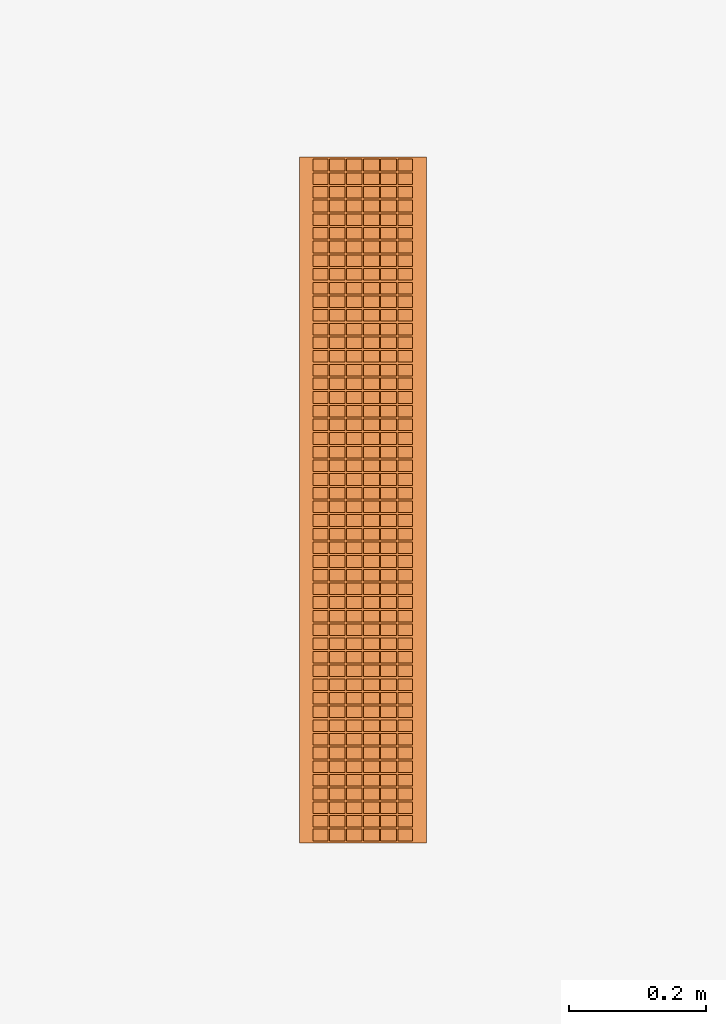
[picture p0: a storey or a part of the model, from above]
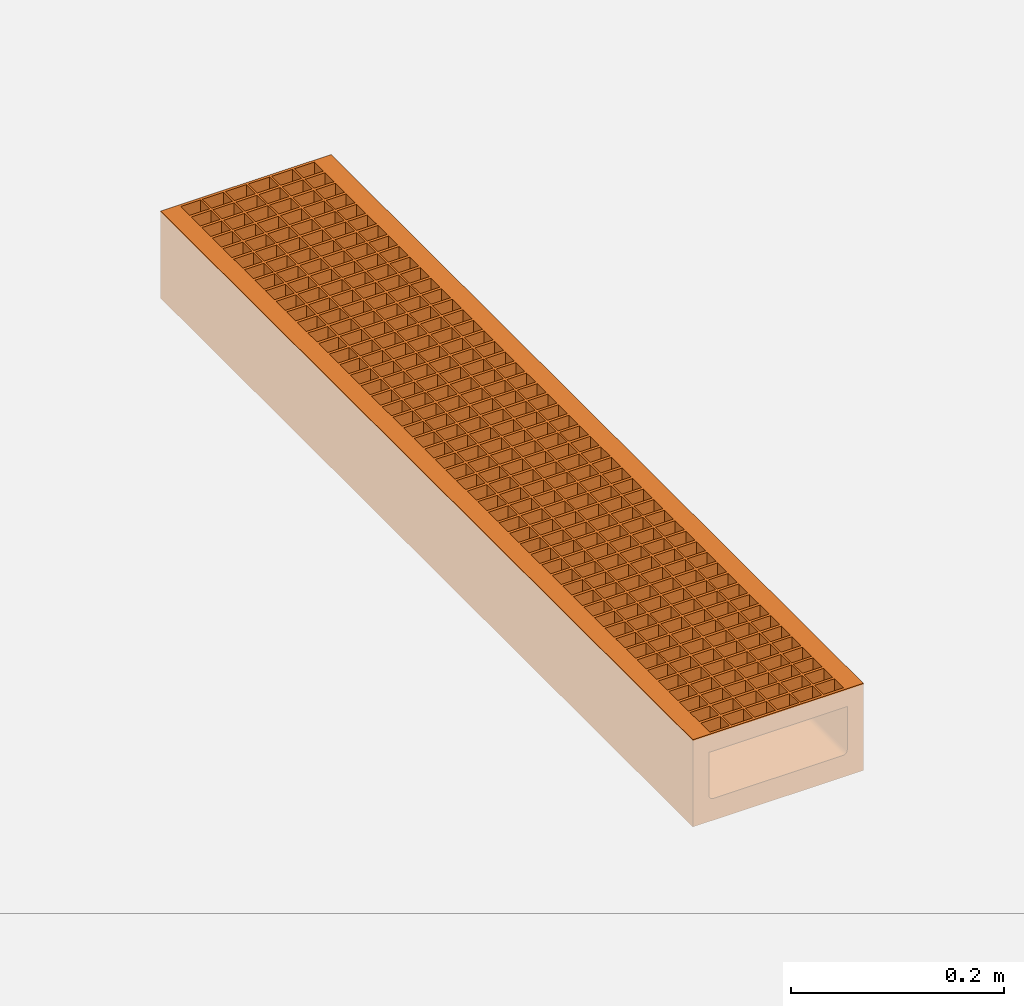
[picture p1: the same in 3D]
Properties of the parts of a building model (IFC2X3)

# File
Description: ViewDefinition [CoordinationView]
File name: 24156 - No 0100 Constant Depth Channel - 1000mm LG - Invert Depth 75mm.ifc
Time: 2013-10-17T16:58:12
Written by: Autodesk Revit 2013
Made in: 20120221_2030(x64)

# IfcProject, Project Number
LongName: Project Name; Phase: Project Status

# IfcSite, Default
RefLatitude: 42, 21, 30, 344238; RefLongitude: -71, -3, -35, -194702; RefElevation: 0 mm

# IfcBuilding
Pset_BuildingCommon - NumberOfStoreys: 1
Other - Project Number: Project Number; Project Address: ## Street City, State Zip; Project Issue Date: Issue Date; Project Status: Project Status; Project Name: Project Name; Client Name: Owner

# IfcBuildingStorey, Level 1
LongName: Level 1; Elevation: 0 mm
Constraints - Elevation Base: 0; Elevation: 0 mm
Graphics - Symbol at End 1 Default: no; Symbol at End 2 Default: yes; Line Pattern: Center; Line Weight: 1; Color: 0; Symbol: M_Level Head - Circle: M_Level Head - Circle
Identity Data - Name: Level 1; Structural: no; Building Story: yes
Dimensions - Computation Height: 0 mm

# IfcBuildingElementProxy: 24156 - No 0100 Constant Depth Channel - 1000mm LG - Invert Depth 75mm, Civil-Drainage-Channel-ACO-MultiDrain-M150DS-Channel-System-Custom_Final FL:24156 - No 0100 Constant Depth Channel - 1000mm LG - Invert Depth 75mm:24156 - No 0100 Constant Depth Channel - 1000mm LG - Invert Depth 75mm:199235
In: Level 1
Material: Vienite® Synthetic Resin Concrete
Constraints - Moves With Nearby Elements: no; Level: Level: Level 1
Phasing - Phase Created: New Construction
Construction - 13048 - Grating - Mesh - Stainless Steel - 1000mm Long: no; 23159 - Universal Endcap (Female End): no; 13049 - Grating - Mesh - Stainless Steel - 500mm Long: no; 23159 - Universal Endcap (Male End): no; Grating_500mm: no; 24157_Shallow Depth Channel with seal: no; Grating_1000mm: yes; Constant Depth Channel_1000: no; 24156_Shallow Depth Channel: yes; Constant Depth Channel_500: no; 24158_Sump Unit: no
Dimensions - EndCap Position: 1000 mm; FloorCut_Length: -1000 mm; Volume: 8023029 mm3; Length: 1000 mm; Custom cut void length: 0 mm; Depth: 310 mm; EndCap_Height: 100 mm; Mesh grating length: -1000 mm; InvDepth: 210 mm; FloorCut_Depth: 100 mm; FloorCut_HorPosition: 92.5 mm; FloorCut_Width: 185 mm
Pset_BuildingElementProxyCommon - Reference: 24156 - No 0100 Constant Depth Channel - 1000mm LG - Invert Depth 75mm
Data - Installation - Concrete Grade: Refer to brochure; Concrete Surround Volume - Load Class A 15 - Concrete Pavement: 0.06m³/m; Invert Depth: 75mm; Product Weight: 16.7Kg; Concrete Surround Volume - Load Class B 125 - C 250 - Concrete Pavement: 0.10m³/m; Load Class: A 15 - D 400; Channel C.S.A: 0.008m²; Concrete Surround Volume - Load Class D 400 - Concrete Pavement: 0.16m³/m; Pre-formed Outlet Ø: N/A; Hydraulic Performance: http://www.aco.co.uk/download.php?id=173; Product Dimensions: 1000mm x 185mm x 100mm (LxWxH); Product Standard: BS EN 1433:2002, CE marked; ACO Hydraulic Design Software: http://www.acodesign.co.uk
General - TagNumber: 0; SerialNumber: 0
Identity Data - Watermark 1: This file is the property of ACO Technologies PLC; Fax: +44 (0)1462 815895; Product brochure: http://www.aco.co.uk/download.php?id=173; e-mail Sales: customersupport@aco.co.uk; Assembly Code: D2040; Telephone: +44 (0)1462 816666; Installation guidelines: http://www.aco.co.uk/download.php?id=173; Manufacturer: ACO Technologies plc - ACO Water Management Division; Address: ACO Business Park, Hitchin Road, Shefford, Bedfordshire, United Kingdom SG17 5TE; Product Page URL: http://www.aco.co.uk/product_detail.php?id=15; Watermark 2: This file is water marked and users are prohibited to reproduce, adapt, distribute this information; Assembly Description: Rain Water Drainage; Type Comments: ACO MultiDrain M150DS 0100 Shallow Constant Depth Channel 1000mm Long; Model Description: Channel drainage system; Watermarked By: www.aco.co.uk; Watermarked With: BIM Manager Premium Suite; Cost: 0; e-mail Technical: technical@aco.co.uk; OmniClass Title: Rainwater Removal; Product Code: 24156; Maintenance guidelines: http://www.aco.co.uk/download.php?id=173; Model: ACO MultiDrain MD - M150DS; Price: POA - contact ACO; OmniClass Number: 23.70.50.24; URL: www.aco.co.uk
Materials and Finishes - Channel Colour: Brown; Edge Rail Colour: Self; Channel Material: Vienite® Synthetic Resin Concrete; Edge Rail Material: Stainless Steel Grade 304
Model Properties - End Cap Product code 23159: No 306 Universal End Cap - 185mm wide x 310mm long - Spigot Ø160mm x 75mm long - Silver - Polypropylene - 0.3kg; Grating Product code 13048: Load Class C250 - Mesh Stainless Steel Grade 304 13048DL 1000mm long - 23x17mm hole - Intake Area 115100mm²/m- 7.4kg; Grating Product code 13049: Load Class C250 - Mesh Stainless Steel Grade 304 13049DL 500mm long - 23x17mm hole - Intake Area 115100mm²/m- 3.7kg
Other - CreatedBy: www.aco.co.uk; Revision: 1
Green Building Properties - Channel Recyclable: Fully recyclable; Edge Rail Recyclable: Fully recyclable; Channel Recycled Material Content: 20% minimum; Edge Rail Recycled Material Content: Between 40% - 90%

# IfcOpeningElement: Recess
In: Level 1
Dimensions - Perimeter: 20000 mm; Thickness: 400 mm; Area: 25000000 mm2; Volume: 9981500000 mm3
Constraints - Room Bounding: yes; Height Offset From Level: 0 mm; Level: Level: Level 1; Related to Mass: no
Structural - Enable Analytical Model: no; Structural: no
Phasing - Phase Created: New Construction
Analytical Properties - Roughness: 1; Absorptance: 0.1
Graphics - Coarse Scale Fill Color: 0
Construction - Function: 0; Default Thickness: 400 mm

# IfcSlab: Floor:Generic Floor - 400mm, Floor:Generic Floor - 400mm:193825
In: Level 1
PredefinedType: FLOOR; Material: Default Roof 400 mm
Dimensions - Perimeter: 20000 mm; Thickness: 400 mm; Area: 25000000 mm2; Volume: 9981500000 mm3
Constraints - Room Bounding: yes; Height Offset From Level: 0 mm; Level: Level: Level 1; Related to Mass: no
Structural - Enable Analytical Model: no; Structural: no
Phasing - Phase Created: New Construction
Pset_SlabCommon - Reference: Generic Floor - 400mm; IsExternal: no; LoadBearing: yes
Analytical Properties - Roughness: 1; Absorptance: 0.1
Graphics - Coarse Scale Fill Color: 0
Construction - Function: 0; Default Thickness: 400 mm
